VERSION 5.7 ;
  NOWIREEXTENSIONATPIN ON ;
  DIVIDERCHAR "/" ;
  BUSBITCHARS "[]" ;
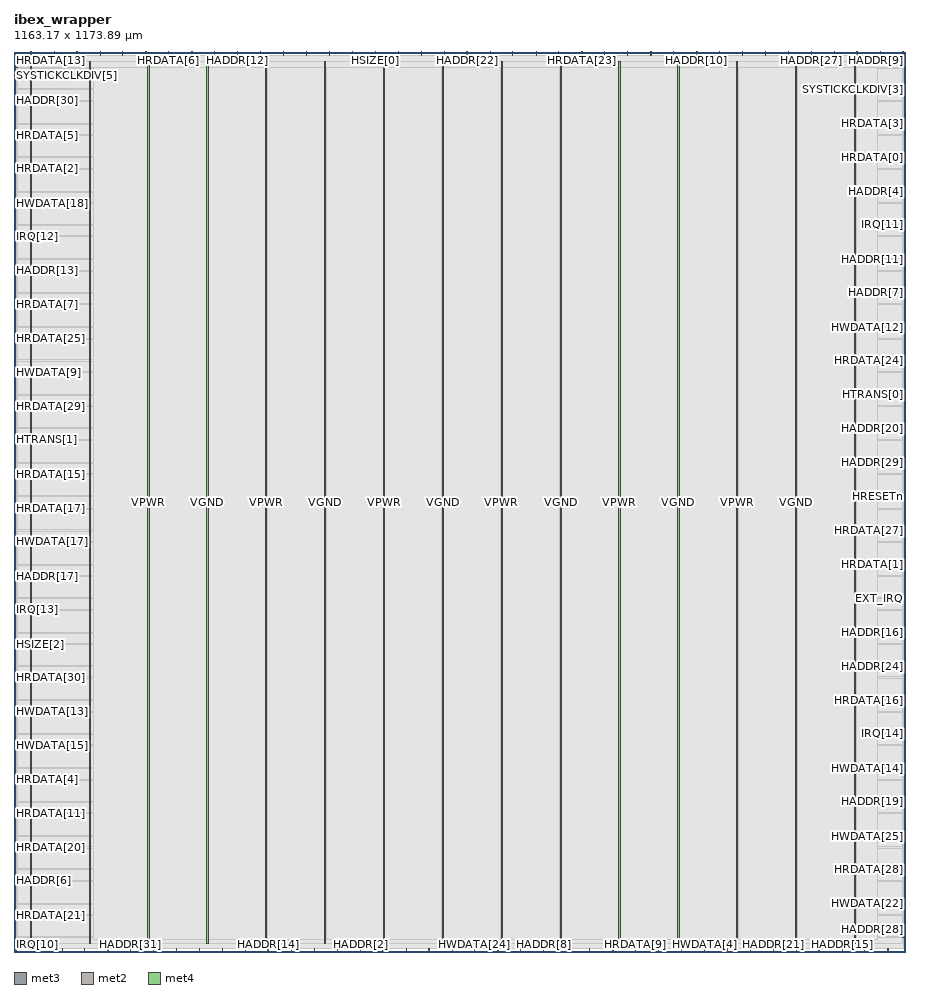
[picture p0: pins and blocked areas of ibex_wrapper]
MACRO ibex_wrapper
  CLASS BLOCK ;
  FOREIGN ibex_wrapper ;
  ORIGIN 0.000 0.000 ;
  SIZE 1163.170 BY 1173.890 ;
  PIN EXT_IRQ
    DIRECTION INPUT ;
    USE SIGNAL ;
    PORT
      LAYER met3 ;
        RECT 1159.170 461.080 1163.170 461.680 ;
    END
  END EXT_IRQ
  PIN HADDR[0]
    DIRECTION OUTPUT TRISTATE ;
    USE SIGNAL ;
    PORT
      LAYER met2 ;
        RECT 52.530 1169.890 52.810 1173.890 ;
    END
  END HADDR[0]
  PIN HADDR[10]
    DIRECTION OUTPUT TRISTATE ;
    USE SIGNAL ;
    PORT
      LAYER met2 ;
        RECT 890.650 1169.890 890.930 1173.890 ;
    END
  END HADDR[10]
  PIN HADDR[11]
    DIRECTION OUTPUT TRISTATE ;
    USE SIGNAL ;
    PORT
      LAYER met3 ;
        RECT 1159.170 903.080 1163.170 903.680 ;
    END
  END HADDR[11]
  PIN HADDR[12]
    DIRECTION OUTPUT TRISTATE ;
    USE SIGNAL ;
    PORT
      LAYER met2 ;
        RECT 291.730 1169.890 292.010 1173.890 ;
    END
  END HADDR[12]
  PIN HADDR[13]
    DIRECTION OUTPUT TRISTATE ;
    USE SIGNAL ;
    PORT
      LAYER met3 ;
        RECT 0.000 888.120 4.000 888.720 ;
    END
  END HADDR[13]
  PIN HADDR[14]
    DIRECTION OUTPUT TRISTATE ;
    USE SIGNAL ;
    PORT
      LAYER met2 ;
        RECT 331.290 0.000 331.570 4.000 ;
    END
  END HADDR[14]
  PIN HADDR[15]
    DIRECTION OUTPUT TRISTATE ;
    USE SIGNAL ;
    PORT
      LAYER met2 ;
        RECT 1080.170 0.000 1080.450 4.000 ;
    END
  END HADDR[15]
  PIN HADDR[16]
    DIRECTION OUTPUT TRISTATE ;
    USE SIGNAL ;
    PORT
      LAYER met3 ;
        RECT 1159.170 416.200 1163.170 416.800 ;
    END
  END HADDR[16]
  PIN HADDR[17]
    DIRECTION OUTPUT TRISTATE ;
    USE SIGNAL ;
    PORT
      LAYER met3 ;
        RECT 0.000 489.640 4.000 490.240 ;
    END
  END HADDR[17]
  PIN HADDR[18]
    DIRECTION OUTPUT TRISTATE ;
    USE SIGNAL ;
    PORT
      LAYER met2 ;
        RECT 81.970 1169.890 82.250 1173.890 ;
    END
  END HADDR[18]
  PIN HADDR[19]
    DIRECTION OUTPUT TRISTATE ;
    USE SIGNAL ;
    PORT
      LAYER met3 ;
        RECT 1159.170 195.880 1163.170 196.480 ;
    END
  END HADDR[19]
  PIN HADDR[1]
    DIRECTION OUTPUT TRISTATE ;
    USE SIGNAL ;
    PORT
      LAYER met2 ;
        RECT 361.650 0.000 361.930 4.000 ;
    END
  END HADDR[1]
  PIN HADDR[20]
    DIRECTION OUTPUT TRISTATE ;
    USE SIGNAL ;
    PORT
      LAYER met3 ;
        RECT 1159.170 682.760 1163.170 683.360 ;
    END
  END HADDR[20]
  PIN HADDR[21]
    DIRECTION OUTPUT TRISTATE ;
    USE SIGNAL ;
    PORT
      LAYER met2 ;
        RECT 990.010 0.000 990.290 4.000 ;
    END
  END HADDR[21]
  PIN HADDR[22]
    DIRECTION OUTPUT TRISTATE ;
    USE SIGNAL ;
    PORT
      LAYER met2 ;
        RECT 590.730 1169.890 591.010 1173.890 ;
    END
  END HADDR[22]
  PIN HADDR[23]
    DIRECTION OUTPUT TRISTATE ;
    USE SIGNAL ;
    PORT
      LAYER met2 ;
        RECT 920.090 1169.890 920.370 1173.890 ;
    END
  END HADDR[23]
  PIN HADDR[24]
    DIRECTION OUTPUT TRISTATE ;
    USE SIGNAL ;
    PORT
      LAYER met3 ;
        RECT 1159.170 372.680 1163.170 373.280 ;
    END
  END HADDR[24]
  PIN HADDR[25]
    DIRECTION OUTPUT TRISTATE ;
    USE SIGNAL ;
    PORT
      LAYER met2 ;
        RECT 571.410 0.000 571.690 4.000 ;
    END
  END HADDR[25]
  PIN HADDR[26]
    DIRECTION OUTPUT TRISTATE ;
    USE SIGNAL ;
    PORT
      LAYER met2 ;
        RECT 750.810 0.000 751.090 4.000 ;
    END
  END HADDR[26]
  PIN HADDR[27]
    DIRECTION OUTPUT TRISTATE ;
    USE SIGNAL ;
    PORT
      LAYER met2 ;
        RECT 1039.690 1169.890 1039.970 1173.890 ;
    END
  END HADDR[27]
  PIN HADDR[28]
    DIRECTION OUTPUT TRISTATE ;
    USE SIGNAL ;
    PORT
      LAYER met3 ;
        RECT 1159.170 19.080 1163.170 19.680 ;
    END
  END HADDR[28]
  PIN HADDR[29]
    DIRECTION OUTPUT TRISTATE ;
    USE SIGNAL ;
    PORT
      LAYER met3 ;
        RECT 1159.170 637.880 1163.170 638.480 ;
    END
  END HADDR[29]
  PIN HADDR[2]
    DIRECTION OUTPUT TRISTATE ;
    USE SIGNAL ;
    PORT
      LAYER met2 ;
        RECT 451.810 0.000 452.090 4.000 ;
    END
  END HADDR[2]
  PIN HADDR[30]
    DIRECTION OUTPUT TRISTATE ;
    USE SIGNAL ;
    PORT
      LAYER met3 ;
        RECT 0.000 1109.800 4.000 1110.400 ;
    END
  END HADDR[30]
  PIN HADDR[31]
    DIRECTION OUTPUT TRISTATE ;
    USE SIGNAL ;
    PORT
      LAYER met2 ;
        RECT 151.890 0.000 152.170 4.000 ;
    END
  END HADDR[31]
  PIN HADDR[3]
    DIRECTION OUTPUT TRISTATE ;
    USE SIGNAL ;
    PORT
      LAYER met2 ;
        RECT 1109.610 0.000 1109.890 4.000 ;
    END
  END HADDR[3]
  PIN HADDR[4]
    DIRECTION OUTPUT TRISTATE ;
    USE SIGNAL ;
    PORT
      LAYER met3 ;
        RECT 1159.170 991.480 1163.170 992.080 ;
    END
  END HADDR[4]
  PIN HADDR[5]
    DIRECTION OUTPUT TRISTATE ;
    USE SIGNAL ;
    PORT
      LAYER met2 ;
        RECT 650.530 1169.890 650.810 1173.890 ;
    END
  END HADDR[5]
  PIN HADDR[6]
    DIRECTION OUTPUT TRISTATE ;
    USE SIGNAL ;
    PORT
      LAYER met3 ;
        RECT 0.000 92.520 4.000 93.120 ;
    END
  END HADDR[6]
  PIN HADDR[7]
    DIRECTION OUTPUT TRISTATE ;
    USE SIGNAL ;
    PORT
      LAYER met3 ;
        RECT 1159.170 859.560 1163.170 860.160 ;
    END
  END HADDR[7]
  PIN HADDR[8]
    DIRECTION OUTPUT TRISTATE ;
    USE SIGNAL ;
    PORT
      LAYER met2 ;
        RECT 691.010 0.000 691.290 4.000 ;
    END
  END HADDR[8]
  PIN HADDR[9]
    DIRECTION OUTPUT TRISTATE ;
    USE SIGNAL ;
    PORT
      LAYER met2 ;
        RECT 1129.850 1169.890 1130.130 1173.890 ;
    END
  END HADDR[9]
  PIN HCLK
    DIRECTION INPUT ;
    USE SIGNAL ;
    PORT
      LAYER met2 ;
        RECT 781.170 0.000 781.450 4.000 ;
    END
  END HCLK
  PIN HRDATA[0]
    DIRECTION INPUT ;
    USE SIGNAL ;
    PORT
      LAYER met3 ;
        RECT 1159.170 1036.360 1163.170 1036.960 ;
    END
  END HRDATA[0]
  PIN HRDATA[10]
    DIRECTION INPUT ;
    USE SIGNAL ;
    PORT
      LAYER met2 ;
        RECT 122.450 0.000 122.730 4.000 ;
    END
  END HRDATA[10]
  PIN HRDATA[11]
    DIRECTION INPUT ;
    USE SIGNAL ;
    PORT
      LAYER met3 ;
        RECT 0.000 180.920 4.000 181.520 ;
    END
  END HRDATA[11]
  PIN HRDATA[12]
    DIRECTION INPUT ;
    USE SIGNAL ;
    PORT
      LAYER met2 ;
        RECT 392.010 0.000 392.290 4.000 ;
    END
  END HRDATA[12]
  PIN HRDATA[13]
    DIRECTION INPUT ;
    USE SIGNAL ;
    PORT
      LAYER met2 ;
        RECT 22.170 1169.890 22.450 1173.890 ;
    END
  END HRDATA[13]
  PIN HRDATA[14]
    DIRECTION INPUT ;
    USE SIGNAL ;
    PORT
      LAYER met2 ;
        RECT 242.050 0.000 242.330 4.000 ;
    END
  END HRDATA[14]
  PIN HRDATA[15]
    DIRECTION INPUT ;
    USE SIGNAL ;
    PORT
      LAYER met3 ;
        RECT 0.000 622.920 4.000 623.520 ;
    END
  END HRDATA[15]
  PIN HRDATA[16]
    DIRECTION INPUT ;
    USE SIGNAL ;
    PORT
      LAYER met3 ;
        RECT 1159.170 327.800 1163.170 328.400 ;
    END
  END HRDATA[16]
  PIN HRDATA[17]
    DIRECTION INPUT ;
    USE SIGNAL ;
    PORT
      LAYER met3 ;
        RECT 0.000 578.040 4.000 578.640 ;
    END
  END HRDATA[17]
  PIN HRDATA[18]
    DIRECTION INPUT ;
    USE SIGNAL ;
    PORT
      LAYER met2 ;
        RECT 960.570 0.000 960.850 4.000 ;
    END
  END HRDATA[18]
  PIN HRDATA[19]
    DIRECTION INPUT ;
    USE SIGNAL ;
    PORT
      LAYER met2 ;
        RECT 631.210 0.000 631.490 4.000 ;
    END
  END HRDATA[19]
  PIN HRDATA[1]
    DIRECTION INPUT ;
    USE SIGNAL ;
    PORT
      LAYER met3 ;
        RECT 1159.170 504.600 1163.170 505.200 ;
    END
  END HRDATA[1]
  PIN HRDATA[20]
    DIRECTION INPUT ;
    USE SIGNAL ;
    PORT
      LAYER met3 ;
        RECT 0.000 136.040 4.000 136.640 ;
    END
  END HRDATA[20]
  PIN HRDATA[21]
    DIRECTION INPUT ;
    USE SIGNAL ;
    PORT
      LAYER met3 ;
        RECT 0.000 47.640 4.000 48.240 ;
    END
  END HRDATA[21]
  PIN HRDATA[22]
    DIRECTION INPUT ;
    USE SIGNAL ;
    PORT
      LAYER met2 ;
        RECT 720.450 0.000 720.730 4.000 ;
    END
  END HRDATA[22]
  PIN HRDATA[23]
    DIRECTION INPUT ;
    USE SIGNAL ;
    PORT
      LAYER met2 ;
        RECT 740.690 1169.890 740.970 1173.890 ;
    END
  END HRDATA[23]
  PIN HRDATA[24]
    DIRECTION INPUT ;
    USE SIGNAL ;
    PORT
      LAYER met3 ;
        RECT 1159.170 771.160 1163.170 771.760 ;
    END
  END HRDATA[24]
  PIN HRDATA[25]
    DIRECTION INPUT ;
    USE SIGNAL ;
    PORT
      LAYER met3 ;
        RECT 0.000 799.720 4.000 800.320 ;
    END
  END HRDATA[25]
  PIN HRDATA[26]
    DIRECTION INPUT ;
    USE SIGNAL ;
    PORT
      LAYER met2 ;
        RECT 870.410 0.000 870.690 4.000 ;
    END
  END HRDATA[26]
  PIN HRDATA[27]
    DIRECTION INPUT ;
    USE SIGNAL ;
    PORT
      LAYER met3 ;
        RECT 1159.170 549.480 1163.170 550.080 ;
    END
  END HRDATA[27]
  PIN HRDATA[28]
    DIRECTION INPUT ;
    USE SIGNAL ;
    PORT
      LAYER met3 ;
        RECT 1159.170 107.480 1163.170 108.080 ;
    END
  END HRDATA[28]
  PIN HRDATA[29]
    DIRECTION INPUT ;
    USE SIGNAL ;
    PORT
      LAYER met3 ;
        RECT 0.000 711.320 4.000 711.920 ;
    END
  END HRDATA[29]
  PIN HRDATA[2]
    DIRECTION INPUT ;
    USE SIGNAL ;
    PORT
      LAYER met3 ;
        RECT 0.000 1021.400 4.000 1022.000 ;
    END
  END HRDATA[2]
  PIN HRDATA[30]
    DIRECTION INPUT ;
    USE SIGNAL ;
    PORT
      LAYER met3 ;
        RECT 0.000 357.720 4.000 358.320 ;
    END
  END HRDATA[30]
  PIN HRDATA[31]
    DIRECTION INPUT ;
    USE SIGNAL ;
    PORT
      LAYER met2 ;
        RECT 211.690 0.000 211.970 4.000 ;
    END
  END HRDATA[31]
  PIN HRDATA[3]
    DIRECTION INPUT ;
    USE SIGNAL ;
    PORT
      LAYER met3 ;
        RECT 1159.170 1079.880 1163.170 1080.480 ;
    END
  END HRDATA[3]
  PIN HRDATA[4]
    DIRECTION INPUT ;
    USE SIGNAL ;
    PORT
      LAYER met3 ;
        RECT 0.000 224.440 4.000 225.040 ;
    END
  END HRDATA[4]
  PIN HRDATA[5]
    DIRECTION INPUT ;
    USE SIGNAL ;
    PORT
      LAYER met3 ;
        RECT 0.000 1064.920 4.000 1065.520 ;
    END
  END HRDATA[5]
  PIN HRDATA[6]
    DIRECTION INPUT ;
    USE SIGNAL ;
    PORT
      LAYER met2 ;
        RECT 201.570 1169.890 201.850 1173.890 ;
    END
  END HRDATA[6]
  PIN HRDATA[7]
    DIRECTION INPUT ;
    USE SIGNAL ;
    PORT
      LAYER met3 ;
        RECT 0.000 844.600 4.000 845.200 ;
    END
  END HRDATA[7]
  PIN HRDATA[8]
    DIRECTION INPUT ;
    USE SIGNAL ;
    PORT
      LAYER met2 ;
        RECT 979.890 1169.890 980.170 1173.890 ;
    END
  END HRDATA[8]
  PIN HRDATA[9]
    DIRECTION INPUT ;
    USE SIGNAL ;
    PORT
      LAYER met2 ;
        RECT 810.610 0.000 810.890 4.000 ;
    END
  END HRDATA[9]
  PIN HREADY
    DIRECTION INPUT ;
    USE SIGNAL ;
    PORT
      LAYER met2 ;
        RECT 261.370 1169.890 261.650 1173.890 ;
    END
  END HREADY
  PIN HRESETn
    DIRECTION INPUT ;
    USE SIGNAL ;
    PORT
      LAYER met3 ;
        RECT 1159.170 594.360 1163.170 594.960 ;
    END
  END HRESETn
  PIN HSIZE[0]
    DIRECTION OUTPUT TRISTATE ;
    USE SIGNAL ;
    PORT
      LAYER met2 ;
        RECT 471.130 1169.890 471.410 1173.890 ;
    END
  END HSIZE[0]
  PIN HSIZE[1]
    DIRECTION OUTPUT TRISTATE ;
    USE SIGNAL ;
    PORT
      LAYER met2 ;
        RECT 1010.250 1169.890 1010.530 1173.890 ;
    END
  END HSIZE[1]
  PIN HSIZE[2]
    DIRECTION OUTPUT TRISTATE ;
    USE SIGNAL ;
    PORT
      LAYER met3 ;
        RECT 0.000 401.240 4.000 401.840 ;
    END
  END HSIZE[2]
  PIN HTRANS[0]
    DIRECTION OUTPUT TRISTATE ;
    USE SIGNAL ;
    PORT
      LAYER met3 ;
        RECT 1159.170 726.280 1163.170 726.880 ;
    END
  END HTRANS[0]
  PIN HTRANS[1]
    DIRECTION OUTPUT TRISTATE ;
    USE SIGNAL ;
    PORT
      LAYER met3 ;
        RECT 0.000 667.800 4.000 668.400 ;
    END
  END HTRANS[1]
  PIN HWDATA[0]
    DIRECTION OUTPUT TRISTATE ;
    USE SIGNAL ;
    PORT
      LAYER met2 ;
        RECT 561.290 1169.890 561.570 1173.890 ;
    END
  END HWDATA[0]
  PIN HWDATA[10]
    DIRECTION OUTPUT TRISTATE ;
    USE SIGNAL ;
    PORT
      LAYER met2 ;
        RECT 380.970 1169.890 381.250 1173.890 ;
    END
  END HWDATA[10]
  PIN HWDATA[11]
    DIRECTION OUTPUT TRISTATE ;
    USE SIGNAL ;
    PORT
      LAYER met2 ;
        RECT 1049.810 0.000 1050.090 4.000 ;
    END
  END HWDATA[11]
  PIN HWDATA[12]
    DIRECTION OUTPUT TRISTATE ;
    USE SIGNAL ;
    PORT
      LAYER met3 ;
        RECT 1159.170 814.680 1163.170 815.280 ;
    END
  END HWDATA[12]
  PIN HWDATA[13]
    DIRECTION OUTPUT TRISTATE ;
    USE SIGNAL ;
    PORT
      LAYER met3 ;
        RECT 0.000 312.840 4.000 313.440 ;
    END
  END HWDATA[13]
  PIN HWDATA[14]
    DIRECTION OUTPUT TRISTATE ;
    USE SIGNAL ;
    PORT
      LAYER met3 ;
        RECT 1159.170 239.400 1163.170 240.000 ;
    END
  END HWDATA[14]
  PIN HWDATA[15]
    DIRECTION OUTPUT TRISTATE ;
    USE SIGNAL ;
    PORT
      LAYER met3 ;
        RECT 0.000 269.320 4.000 269.920 ;
    END
  END HWDATA[15]
  PIN HWDATA[16]
    DIRECTION OUTPUT TRISTATE ;
    USE SIGNAL ;
    PORT
      LAYER met2 ;
        RECT 321.170 1169.890 321.450 1173.890 ;
    END
  END HWDATA[16]
  PIN HWDATA[17]
    DIRECTION OUTPUT TRISTATE ;
    USE SIGNAL ;
    PORT
      LAYER met3 ;
        RECT 0.000 534.520 4.000 535.120 ;
    END
  END HWDATA[17]
  PIN HWDATA[18]
    DIRECTION OUTPUT TRISTATE ;
    USE SIGNAL ;
    PORT
      LAYER met3 ;
        RECT 0.000 976.520 4.000 977.120 ;
    END
  END HWDATA[18]
  PIN HWDATA[19]
    DIRECTION OUTPUT TRISTATE ;
    USE SIGNAL ;
    PORT
      LAYER met2 ;
        RECT 501.490 1169.890 501.770 1173.890 ;
    END
  END HWDATA[19]
  PIN HWDATA[1]
    DIRECTION OUTPUT TRISTATE ;
    USE SIGNAL ;
    PORT
      LAYER met2 ;
        RECT 62.650 0.000 62.930 4.000 ;
    END
  END HWDATA[1]
  PIN HWDATA[20]
    DIRECTION OUTPUT TRISTATE ;
    USE SIGNAL ;
    PORT
      LAYER met2 ;
        RECT 511.610 0.000 511.890 4.000 ;
    END
  END HWDATA[20]
  PIN HWDATA[21]
    DIRECTION OUTPUT TRISTATE ;
    USE SIGNAL ;
    PORT
      LAYER met2 ;
        RECT 1070.050 1169.890 1070.330 1173.890 ;
    END
  END HWDATA[21]
  PIN HWDATA[22]
    DIRECTION OUTPUT TRISTATE ;
    USE SIGNAL ;
    PORT
      LAYER met3 ;
        RECT 1159.170 62.600 1163.170 63.200 ;
    END
  END HWDATA[22]
  PIN HWDATA[23]
    DIRECTION OUTPUT TRISTATE ;
    USE SIGNAL ;
    PORT
      LAYER met2 ;
        RECT 112.330 1169.890 112.610 1173.890 ;
    END
  END HWDATA[23]
  PIN HWDATA[24]
    DIRECTION OUTPUT TRISTATE ;
    USE SIGNAL ;
    PORT
      LAYER met2 ;
        RECT 600.850 0.000 601.130 4.000 ;
    END
  END HWDATA[24]
  PIN HWDATA[25]
    DIRECTION OUTPUT TRISTATE ;
    USE SIGNAL ;
    PORT
      LAYER met3 ;
        RECT 1159.170 151.000 1163.170 151.600 ;
    END
  END HWDATA[25]
  PIN HWDATA[26]
    DIRECTION OUTPUT TRISTATE ;
    USE SIGNAL ;
    PORT
      LAYER met2 ;
        RECT 351.530 1169.890 351.810 1173.890 ;
    END
  END HWDATA[26]
  PIN HWDATA[27]
    DIRECTION OUTPUT TRISTATE ;
    USE SIGNAL ;
    PORT
      LAYER met2 ;
        RECT 411.330 1169.890 411.610 1173.890 ;
    END
  END HWDATA[27]
  PIN HWDATA[28]
    DIRECTION OUTPUT TRISTATE ;
    USE SIGNAL ;
    PORT
      LAYER met2 ;
        RECT 660.650 0.000 660.930 4.000 ;
    END
  END HWDATA[28]
  PIN HWDATA[29]
    DIRECTION OUTPUT TRISTATE ;
    USE SIGNAL ;
    PORT
      LAYER met2 ;
        RECT 1020.370 0.000 1020.650 4.000 ;
    END
  END HWDATA[29]
  PIN HWDATA[2]
    DIRECTION OUTPUT TRISTATE ;
    USE SIGNAL ;
    PORT
      LAYER met2 ;
        RECT 1099.490 1169.890 1099.770 1173.890 ;
    END
  END HWDATA[2]
  PIN HWDATA[30]
    DIRECTION OUTPUT TRISTATE ;
    USE SIGNAL ;
    PORT
      LAYER met2 ;
        RECT 1139.970 0.000 1140.250 4.000 ;
    END
  END HWDATA[30]
  PIN HWDATA[31]
    DIRECTION OUTPUT TRISTATE ;
    USE SIGNAL ;
    PORT
      LAYER met2 ;
        RECT 541.050 0.000 541.330 4.000 ;
    END
  END HWDATA[31]
  PIN HWDATA[3]
    DIRECTION OUTPUT TRISTATE ;
    USE SIGNAL ;
    PORT
      LAYER met2 ;
        RECT 441.690 1169.890 441.970 1173.890 ;
    END
  END HWDATA[3]
  PIN HWDATA[4]
    DIRECTION OUTPUT TRISTATE ;
    USE SIGNAL ;
    PORT
      LAYER met2 ;
        RECT 900.770 0.000 901.050 4.000 ;
    END
  END HWDATA[4]
  PIN HWDATA[5]
    DIRECTION OUTPUT TRISTATE ;
    USE SIGNAL ;
    PORT
      LAYER met2 ;
        RECT 840.970 0.000 841.250 4.000 ;
    END
  END HWDATA[5]
  PIN HWDATA[6]
    DIRECTION OUTPUT TRISTATE ;
    USE SIGNAL ;
    PORT
      LAYER met2 ;
        RECT 710.330 1169.890 710.610 1173.890 ;
    END
  END HWDATA[6]
  PIN HWDATA[7]
    DIRECTION OUTPUT TRISTATE ;
    USE SIGNAL ;
    PORT
      LAYER met2 ;
        RECT 621.090 1169.890 621.370 1173.890 ;
    END
  END HWDATA[7]
  PIN HWDATA[8]
    DIRECTION OUTPUT TRISTATE ;
    USE SIGNAL ;
    PORT
      LAYER met2 ;
        RECT 680.890 1169.890 681.170 1173.890 ;
    END
  END HWDATA[8]
  PIN HWDATA[9]
    DIRECTION OUTPUT TRISTATE ;
    USE SIGNAL ;
    PORT
      LAYER met3 ;
        RECT 0.000 756.200 4.000 756.800 ;
    END
  END HWDATA[9]
  PIN HWRITE
    DIRECTION OUTPUT TRISTATE ;
    USE SIGNAL ;
    PORT
      LAYER met2 ;
        RECT 860.290 1169.890 860.570 1173.890 ;
    END
  END HWRITE
  PIN IRQ[0]
    DIRECTION INPUT ;
    USE SIGNAL ;
    PORT
      LAYER met2 ;
        RECT 421.450 0.000 421.730 4.000 ;
    END
  END IRQ[0]
  PIN IRQ[10]
    DIRECTION INPUT ;
    USE SIGNAL ;
    PORT
      LAYER met2 ;
        RECT 2.850 0.000 3.130 4.000 ;
    END
  END IRQ[10]
  PIN IRQ[11]
    DIRECTION INPUT ;
    USE SIGNAL ;
    PORT
      LAYER met3 ;
        RECT 1159.170 947.960 1163.170 948.560 ;
    END
  END IRQ[11]
  PIN IRQ[12]
    DIRECTION INPUT ;
    USE SIGNAL ;
    PORT
      LAYER met3 ;
        RECT 0.000 933.000 4.000 933.600 ;
    END
  END IRQ[12]
  PIN IRQ[13]
    DIRECTION INPUT ;
    USE SIGNAL ;
    PORT
      LAYER met3 ;
        RECT 0.000 446.120 4.000 446.720 ;
    END
  END IRQ[13]
  PIN IRQ[14]
    DIRECTION INPUT ;
    USE SIGNAL ;
    PORT
      LAYER met3 ;
        RECT 1159.170 284.280 1163.170 284.880 ;
    END
  END IRQ[14]
  PIN IRQ[1]
    DIRECTION INPUT ;
    USE SIGNAL ;
    PORT
      LAYER met2 ;
        RECT 141.770 1169.890 142.050 1173.890 ;
    END
  END IRQ[1]
  PIN IRQ[2]
    DIRECTION INPUT ;
    USE SIGNAL ;
    PORT
      LAYER met2 ;
        RECT 231.930 1169.890 232.210 1173.890 ;
    END
  END IRQ[2]
  PIN IRQ[3]
    DIRECTION INPUT ;
    USE SIGNAL ;
    PORT
      LAYER met2 ;
        RECT 530.930 1169.890 531.210 1173.890 ;
    END
  END IRQ[3]
  PIN IRQ[4]
    DIRECTION INPUT ;
    USE SIGNAL ;
    PORT
      LAYER met2 ;
        RECT 172.130 1169.890 172.410 1173.890 ;
    END
  END IRQ[4]
  PIN IRQ[5]
    DIRECTION INPUT ;
    USE SIGNAL ;
    PORT
      LAYER met2 ;
        RECT 182.250 0.000 182.530 4.000 ;
    END
  END IRQ[5]
  PIN IRQ[6]
    DIRECTION INPUT ;
    USE SIGNAL ;
    PORT
      LAYER met2 ;
        RECT 32.290 0.000 32.570 4.000 ;
    END
  END IRQ[6]
  PIN IRQ[7]
    DIRECTION INPUT ;
    USE SIGNAL ;
    PORT
      LAYER met2 ;
        RECT 800.490 1169.890 800.770 1173.890 ;
    END
  END IRQ[7]
  PIN IRQ[8]
    DIRECTION INPUT ;
    USE SIGNAL ;
    PORT
      LAYER met2 ;
        RECT 830.850 1169.890 831.130 1173.890 ;
    END
  END IRQ[8]
  PIN IRQ[9]
    DIRECTION INPUT ;
    USE SIGNAL ;
    PORT
      LAYER met2 ;
        RECT 271.490 0.000 271.770 4.000 ;
    END
  END IRQ[9]
  PIN NMI
    DIRECTION INPUT ;
    USE SIGNAL ;
    PORT
      LAYER met2 ;
        RECT 481.250 0.000 481.530 4.000 ;
    END
  END NMI
  PIN SYSTICKCLKDIV[0]
    DIRECTION INPUT ;
    USE SIGNAL ;
    PORT
      LAYER met2 ;
        RECT 1159.290 1169.890 1159.570 1173.890 ;
    END
  END SYSTICKCLKDIV[0]
  PIN SYSTICKCLKDIV[1]
    DIRECTION INPUT ;
    USE SIGNAL ;
    PORT
      LAYER met2 ;
        RECT 301.850 0.000 302.130 4.000 ;
    END
  END SYSTICKCLKDIV[1]
  PIN SYSTICKCLKDIV[2]
    DIRECTION INPUT ;
    USE SIGNAL ;
    PORT
      LAYER met2 ;
        RECT 950.450 1169.890 950.730 1173.890 ;
    END
  END SYSTICKCLKDIV[2]
  PIN SYSTICKCLKDIV[3]
    DIRECTION INPUT ;
    USE SIGNAL ;
    PORT
      LAYER met3 ;
        RECT 1159.170 1124.760 1163.170 1125.360 ;
    END
  END SYSTICKCLKDIV[3]
  PIN SYSTICKCLKDIV[4]
    DIRECTION INPUT ;
    USE SIGNAL ;
    PORT
      LAYER met2 ;
        RECT 92.090 0.000 92.370 4.000 ;
    END
  END SYSTICKCLKDIV[4]
  PIN SYSTICKCLKDIV[5]
    DIRECTION INPUT ;
    USE SIGNAL ;
    PORT
      LAYER met3 ;
        RECT 0.000 1153.320 4.000 1153.920 ;
    END
  END SYSTICKCLKDIV[5]
  PIN SYSTICKCLKDIV[6]
    DIRECTION INPUT ;
    USE SIGNAL ;
    PORT
      LAYER met2 ;
        RECT 770.130 1169.890 770.410 1173.890 ;
    END
  END SYSTICKCLKDIV[6]
  PIN SYSTICKCLKDIV[7]
    DIRECTION INPUT ;
    USE SIGNAL ;
    PORT
      LAYER met2 ;
        RECT 930.210 0.000 930.490 4.000 ;
    END
  END SYSTICKCLKDIV[7]
  PIN VPWR
    DIRECTION INOUT ;
    USE POWER ;
    PORT
      LAYER met4 ;
        RECT 1096.240 10.640 1097.840 1161.680 ;
    END
  END VPWR
  PIN VPWR
    DIRECTION INOUT ;
    USE POWER ;
    PORT
      LAYER met4 ;
        RECT 942.640 10.640 944.240 1161.680 ;
    END
  END VPWR
  PIN VPWR
    DIRECTION INOUT ;
    USE POWER ;
    PORT
      LAYER met4 ;
        RECT 789.040 10.640 790.640 1161.680 ;
    END
  END VPWR
  PIN VPWR
    DIRECTION INOUT ;
    USE POWER ;
    PORT
      LAYER met4 ;
        RECT 635.440 10.640 637.040 1161.680 ;
    END
  END VPWR
  PIN VPWR
    DIRECTION INOUT ;
    USE POWER ;
    PORT
      LAYER met4 ;
        RECT 481.840 10.640 483.440 1161.680 ;
    END
  END VPWR
  PIN VPWR
    DIRECTION INOUT ;
    USE POWER ;
    PORT
      LAYER met4 ;
        RECT 328.240 10.640 329.840 1161.680 ;
    END
  END VPWR
  PIN VPWR
    DIRECTION INOUT ;
    USE POWER ;
    PORT
      LAYER met4 ;
        RECT 174.640 10.640 176.240 1161.680 ;
    END
  END VPWR
  PIN VPWR
    DIRECTION INOUT ;
    USE POWER ;
    PORT
      LAYER met4 ;
        RECT 21.040 10.640 22.640 1161.680 ;
    END
  END VPWR
  PIN VGND
    DIRECTION INOUT ;
    USE GROUND ;
    PORT
      LAYER met4 ;
        RECT 1019.440 10.640 1021.040 1161.680 ;
    END
  END VGND
  PIN VGND
    DIRECTION INOUT ;
    USE GROUND ;
    PORT
      LAYER met4 ;
        RECT 865.840 10.640 867.440 1161.680 ;
    END
  END VGND
  PIN VGND
    DIRECTION INOUT ;
    USE GROUND ;
    PORT
      LAYER met4 ;
        RECT 712.240 10.640 713.840 1161.680 ;
    END
  END VGND
  PIN VGND
    DIRECTION INOUT ;
    USE GROUND ;
    PORT
      LAYER met4 ;
        RECT 558.640 10.640 560.240 1161.680 ;
    END
  END VGND
  PIN VGND
    DIRECTION INOUT ;
    USE GROUND ;
    PORT
      LAYER met4 ;
        RECT 405.040 10.640 406.640 1161.680 ;
    END
  END VGND
  PIN VGND
    DIRECTION INOUT ;
    USE GROUND ;
    PORT
      LAYER met4 ;
        RECT 251.440 10.640 253.040 1161.680 ;
    END
  END VGND
  PIN VGND
    DIRECTION INOUT ;
    USE GROUND ;
    PORT
      LAYER met4 ;
        RECT 97.840 10.640 99.440 1161.680 ;
    END
  END VGND
  OBS
      LAYER li1 ;
        RECT 5.520 10.795 1157.360 1161.525 ;
      LAYER met1 ;
        RECT 2.830 4.460 1159.590 1169.560 ;
      LAYER met2 ;
        RECT 2.860 1169.610 21.890 1169.890 ;
        RECT 22.730 1169.610 52.250 1169.890 ;
        RECT 53.090 1169.610 81.690 1169.890 ;
        RECT 82.530 1169.610 112.050 1169.890 ;
        RECT 112.890 1169.610 141.490 1169.890 ;
        RECT 142.330 1169.610 171.850 1169.890 ;
        RECT 172.690 1169.610 201.290 1169.890 ;
        RECT 202.130 1169.610 231.650 1169.890 ;
        RECT 232.490 1169.610 261.090 1169.890 ;
        RECT 261.930 1169.610 291.450 1169.890 ;
        RECT 292.290 1169.610 320.890 1169.890 ;
        RECT 321.730 1169.610 351.250 1169.890 ;
        RECT 352.090 1169.610 380.690 1169.890 ;
        RECT 381.530 1169.610 411.050 1169.890 ;
        RECT 411.890 1169.610 441.410 1169.890 ;
        RECT 442.250 1169.610 470.850 1169.890 ;
        RECT 471.690 1169.610 501.210 1169.890 ;
        RECT 502.050 1169.610 530.650 1169.890 ;
        RECT 531.490 1169.610 561.010 1169.890 ;
        RECT 561.850 1169.610 590.450 1169.890 ;
        RECT 591.290 1169.610 620.810 1169.890 ;
        RECT 621.650 1169.610 650.250 1169.890 ;
        RECT 651.090 1169.610 680.610 1169.890 ;
        RECT 681.450 1169.610 710.050 1169.890 ;
        RECT 710.890 1169.610 740.410 1169.890 ;
        RECT 741.250 1169.610 769.850 1169.890 ;
        RECT 770.690 1169.610 800.210 1169.890 ;
        RECT 801.050 1169.610 830.570 1169.890 ;
        RECT 831.410 1169.610 860.010 1169.890 ;
        RECT 860.850 1169.610 890.370 1169.890 ;
        RECT 891.210 1169.610 919.810 1169.890 ;
        RECT 920.650 1169.610 950.170 1169.890 ;
        RECT 951.010 1169.610 979.610 1169.890 ;
        RECT 980.450 1169.610 1009.970 1169.890 ;
        RECT 1010.810 1169.610 1039.410 1169.890 ;
        RECT 1040.250 1169.610 1069.770 1169.890 ;
        RECT 1070.610 1169.610 1099.210 1169.890 ;
        RECT 1100.050 1169.610 1129.570 1169.890 ;
        RECT 1130.410 1169.610 1159.010 1169.890 ;
        RECT 2.860 4.280 1159.560 1169.610 ;
        RECT 3.410 4.000 32.010 4.280 ;
        RECT 32.850 4.000 62.370 4.280 ;
        RECT 63.210 4.000 91.810 4.280 ;
        RECT 92.650 4.000 122.170 4.280 ;
        RECT 123.010 4.000 151.610 4.280 ;
        RECT 152.450 4.000 181.970 4.280 ;
        RECT 182.810 4.000 211.410 4.280 ;
        RECT 212.250 4.000 241.770 4.280 ;
        RECT 242.610 4.000 271.210 4.280 ;
        RECT 272.050 4.000 301.570 4.280 ;
        RECT 302.410 4.000 331.010 4.280 ;
        RECT 331.850 4.000 361.370 4.280 ;
        RECT 362.210 4.000 391.730 4.280 ;
        RECT 392.570 4.000 421.170 4.280 ;
        RECT 422.010 4.000 451.530 4.280 ;
        RECT 452.370 4.000 480.970 4.280 ;
        RECT 481.810 4.000 511.330 4.280 ;
        RECT 512.170 4.000 540.770 4.280 ;
        RECT 541.610 4.000 571.130 4.280 ;
        RECT 571.970 4.000 600.570 4.280 ;
        RECT 601.410 4.000 630.930 4.280 ;
        RECT 631.770 4.000 660.370 4.280 ;
        RECT 661.210 4.000 690.730 4.280 ;
        RECT 691.570 4.000 720.170 4.280 ;
        RECT 721.010 4.000 750.530 4.280 ;
        RECT 751.370 4.000 780.890 4.280 ;
        RECT 781.730 4.000 810.330 4.280 ;
        RECT 811.170 4.000 840.690 4.280 ;
        RECT 841.530 4.000 870.130 4.280 ;
        RECT 870.970 4.000 900.490 4.280 ;
        RECT 901.330 4.000 929.930 4.280 ;
        RECT 930.770 4.000 960.290 4.280 ;
        RECT 961.130 4.000 989.730 4.280 ;
        RECT 990.570 4.000 1020.090 4.280 ;
        RECT 1020.930 4.000 1049.530 4.280 ;
        RECT 1050.370 4.000 1079.890 4.280 ;
        RECT 1080.730 4.000 1109.330 4.280 ;
        RECT 1110.170 4.000 1139.690 4.280 ;
        RECT 1140.530 4.000 1159.560 4.280 ;
      LAYER met3 ;
        RECT 4.000 1154.320 1159.170 1161.605 ;
        RECT 4.400 1152.920 1159.170 1154.320 ;
        RECT 4.000 1125.760 1159.170 1152.920 ;
        RECT 4.000 1124.360 1158.770 1125.760 ;
        RECT 4.000 1110.800 1159.170 1124.360 ;
        RECT 4.400 1109.400 1159.170 1110.800 ;
        RECT 4.000 1080.880 1159.170 1109.400 ;
        RECT 4.000 1079.480 1158.770 1080.880 ;
        RECT 4.000 1065.920 1159.170 1079.480 ;
        RECT 4.400 1064.520 1159.170 1065.920 ;
        RECT 4.000 1037.360 1159.170 1064.520 ;
        RECT 4.000 1035.960 1158.770 1037.360 ;
        RECT 4.000 1022.400 1159.170 1035.960 ;
        RECT 4.400 1021.000 1159.170 1022.400 ;
        RECT 4.000 992.480 1159.170 1021.000 ;
        RECT 4.000 991.080 1158.770 992.480 ;
        RECT 4.000 977.520 1159.170 991.080 ;
        RECT 4.400 976.120 1159.170 977.520 ;
        RECT 4.000 948.960 1159.170 976.120 ;
        RECT 4.000 947.560 1158.770 948.960 ;
        RECT 4.000 934.000 1159.170 947.560 ;
        RECT 4.400 932.600 1159.170 934.000 ;
        RECT 4.000 904.080 1159.170 932.600 ;
        RECT 4.000 902.680 1158.770 904.080 ;
        RECT 4.000 889.120 1159.170 902.680 ;
        RECT 4.400 887.720 1159.170 889.120 ;
        RECT 4.000 860.560 1159.170 887.720 ;
        RECT 4.000 859.160 1158.770 860.560 ;
        RECT 4.000 845.600 1159.170 859.160 ;
        RECT 4.400 844.200 1159.170 845.600 ;
        RECT 4.000 815.680 1159.170 844.200 ;
        RECT 4.000 814.280 1158.770 815.680 ;
        RECT 4.000 800.720 1159.170 814.280 ;
        RECT 4.400 799.320 1159.170 800.720 ;
        RECT 4.000 772.160 1159.170 799.320 ;
        RECT 4.000 770.760 1158.770 772.160 ;
        RECT 4.000 757.200 1159.170 770.760 ;
        RECT 4.400 755.800 1159.170 757.200 ;
        RECT 4.000 727.280 1159.170 755.800 ;
        RECT 4.000 725.880 1158.770 727.280 ;
        RECT 4.000 712.320 1159.170 725.880 ;
        RECT 4.400 710.920 1159.170 712.320 ;
        RECT 4.000 683.760 1159.170 710.920 ;
        RECT 4.000 682.360 1158.770 683.760 ;
        RECT 4.000 668.800 1159.170 682.360 ;
        RECT 4.400 667.400 1159.170 668.800 ;
        RECT 4.000 638.880 1159.170 667.400 ;
        RECT 4.000 637.480 1158.770 638.880 ;
        RECT 4.000 623.920 1159.170 637.480 ;
        RECT 4.400 622.520 1159.170 623.920 ;
        RECT 4.000 595.360 1159.170 622.520 ;
        RECT 4.000 593.960 1158.770 595.360 ;
        RECT 4.000 579.040 1159.170 593.960 ;
        RECT 4.400 577.640 1159.170 579.040 ;
        RECT 4.000 550.480 1159.170 577.640 ;
        RECT 4.000 549.080 1158.770 550.480 ;
        RECT 4.000 535.520 1159.170 549.080 ;
        RECT 4.400 534.120 1159.170 535.520 ;
        RECT 4.000 505.600 1159.170 534.120 ;
        RECT 4.000 504.200 1158.770 505.600 ;
        RECT 4.000 490.640 1159.170 504.200 ;
        RECT 4.400 489.240 1159.170 490.640 ;
        RECT 4.000 462.080 1159.170 489.240 ;
        RECT 4.000 460.680 1158.770 462.080 ;
        RECT 4.000 447.120 1159.170 460.680 ;
        RECT 4.400 445.720 1159.170 447.120 ;
        RECT 4.000 417.200 1159.170 445.720 ;
        RECT 4.000 415.800 1158.770 417.200 ;
        RECT 4.000 402.240 1159.170 415.800 ;
        RECT 4.400 400.840 1159.170 402.240 ;
        RECT 4.000 373.680 1159.170 400.840 ;
        RECT 4.000 372.280 1158.770 373.680 ;
        RECT 4.000 358.720 1159.170 372.280 ;
        RECT 4.400 357.320 1159.170 358.720 ;
        RECT 4.000 328.800 1159.170 357.320 ;
        RECT 4.000 327.400 1158.770 328.800 ;
        RECT 4.000 313.840 1159.170 327.400 ;
        RECT 4.400 312.440 1159.170 313.840 ;
        RECT 4.000 285.280 1159.170 312.440 ;
        RECT 4.000 283.880 1158.770 285.280 ;
        RECT 4.000 270.320 1159.170 283.880 ;
        RECT 4.400 268.920 1159.170 270.320 ;
        RECT 4.000 240.400 1159.170 268.920 ;
        RECT 4.000 239.000 1158.770 240.400 ;
        RECT 4.000 225.440 1159.170 239.000 ;
        RECT 4.400 224.040 1159.170 225.440 ;
        RECT 4.000 196.880 1159.170 224.040 ;
        RECT 4.000 195.480 1158.770 196.880 ;
        RECT 4.000 181.920 1159.170 195.480 ;
        RECT 4.400 180.520 1159.170 181.920 ;
        RECT 4.000 152.000 1159.170 180.520 ;
        RECT 4.000 150.600 1158.770 152.000 ;
        RECT 4.000 137.040 1159.170 150.600 ;
        RECT 4.400 135.640 1159.170 137.040 ;
        RECT 4.000 108.480 1159.170 135.640 ;
        RECT 4.000 107.080 1158.770 108.480 ;
        RECT 4.000 93.520 1159.170 107.080 ;
        RECT 4.400 92.120 1159.170 93.520 ;
        RECT 4.000 63.600 1159.170 92.120 ;
        RECT 4.000 62.200 1158.770 63.600 ;
        RECT 4.000 48.640 1159.170 62.200 ;
        RECT 4.400 47.240 1159.170 48.640 ;
        RECT 4.000 20.080 1159.170 47.240 ;
        RECT 4.000 18.680 1158.770 20.080 ;
        RECT 4.000 10.715 1159.170 18.680 ;
      LAYER met4 ;
        RECT 103.335 16.495 174.240 1153.105 ;
        RECT 176.640 16.495 251.040 1153.105 ;
        RECT 253.440 16.495 327.840 1153.105 ;
        RECT 330.240 16.495 404.640 1153.105 ;
        RECT 407.040 16.495 481.440 1153.105 ;
        RECT 483.840 16.495 558.240 1153.105 ;
        RECT 560.640 16.495 635.040 1153.105 ;
        RECT 637.440 16.495 711.840 1153.105 ;
        RECT 714.240 16.495 788.640 1153.105 ;
        RECT 791.040 16.495 865.440 1153.105 ;
        RECT 867.840 16.495 942.240 1153.105 ;
        RECT 944.640 16.495 1019.040 1153.105 ;
        RECT 1021.440 16.495 1095.840 1153.105 ;
        RECT 1098.240 16.495 1125.785 1153.105 ;
  END
END ibex_wrapper
END LIBRARY

